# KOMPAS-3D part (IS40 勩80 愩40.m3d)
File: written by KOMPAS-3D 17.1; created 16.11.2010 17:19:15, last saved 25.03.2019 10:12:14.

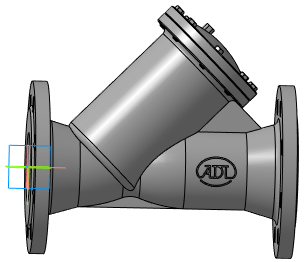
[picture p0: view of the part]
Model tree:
1. Плоскость XY
2. Плоскость ZX
3. Плоскость ZY
4. Ось X
5. Ось Y
6. Ось Z
7. Начало координат
8. Операция без истории:2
